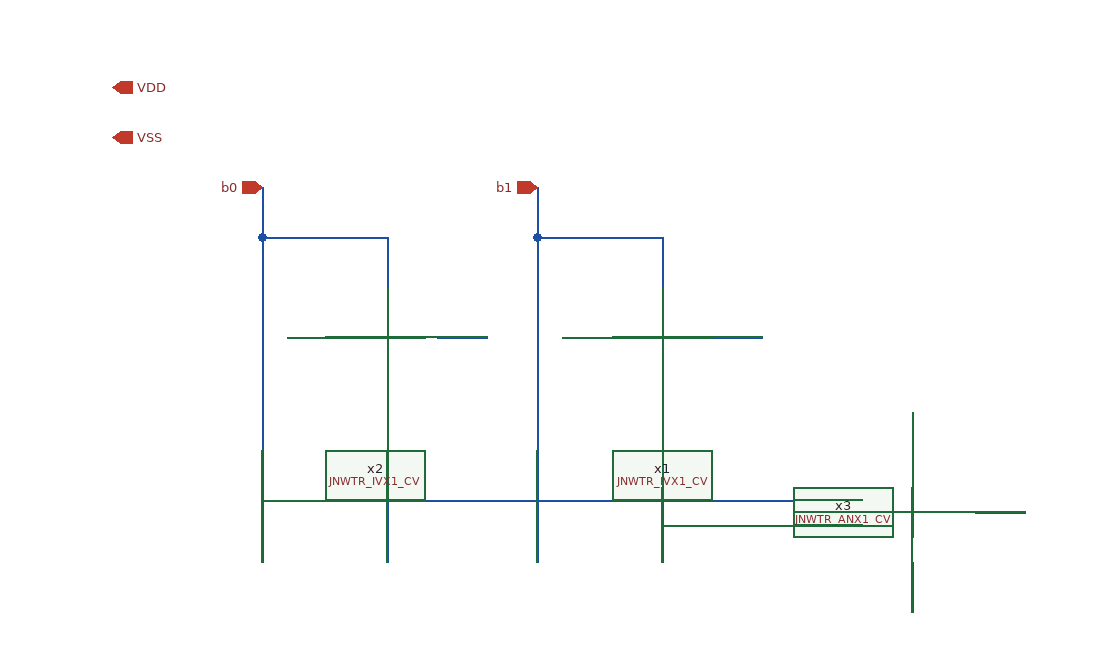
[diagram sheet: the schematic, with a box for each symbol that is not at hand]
v {xschem version=3.4.6 file_version=1.2}
G {}
K {}
V {}
S {}
E {}
N 340 180 340 220 {lab=b0}
N 240 180 340 180 {lab=b0}
N 240 180 240 440 {lab=b0}
N 340 300 340 440 {lab=#net1}
N 240 140 240 180 {lab=b0}
N 260 260 300 260 {lab=#net2}
N 380 260 420 260 {lab=#net3}
N 560 180 560 220 {lab=b1}
N 460 180 560 180 {lab=b1}
N 460 180 460 440 {lab=b1}
N 560 300 560 440 {lab=#net4}
N 460 140 460 180 {lab=b1}
N 480 260 520 260 {lab=#net5}
N 600 260 640 260 {lab=#net6}
N 760 320 760 360 {lab=#net7}
N 760 440 760 480 {lab=#net8}
N 240 390 720 390 {lab=#net9}
N 560 410 720 410 {lab=#net10}
N 810 400 850 400 {lab=#net11}
C {JNW_TR_SKY130A/JNWTR_IVX1_CV.sym} 340 220 3 1 {name=x2 }
C {JNW_TR_SKY130A/JNWTR_IVX1_CV.sym} 560 220 3 1 {name=x1 }
C {devices/ipin.sym} 240 140 1 0 {name=p2 lab=b0}
C {devices/ipin.sym} 460 140 1 0 {name=p3 lab=b1}
C {devices/ipin.sym} 120 60 2 1 {name=p9 lab=VDD}
C {devices/ipin.sym} 120 100 2 1 {name=p10 lab=VSS}
C {JNW_TR_SKY130A/JNWTR_ANX1_CV.sym} 720 410 0 0 {name=x3 }
